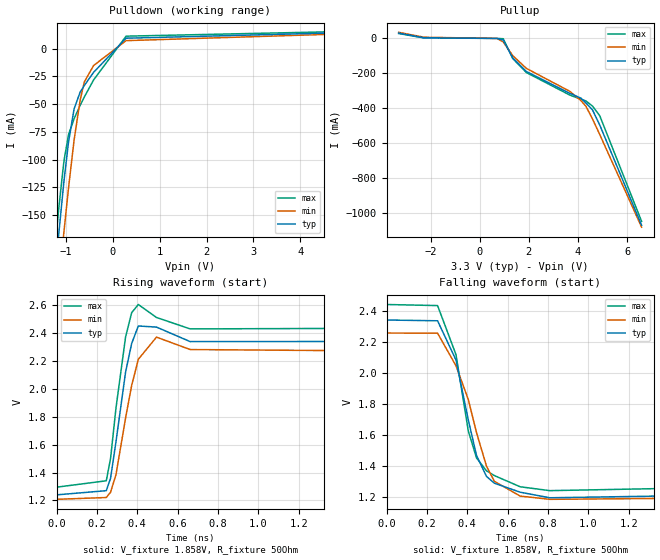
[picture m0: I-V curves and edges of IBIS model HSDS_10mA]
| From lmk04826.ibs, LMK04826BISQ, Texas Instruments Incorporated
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[Model]   HSDS_10mA
Model_type   Output
Polarity   Non-Inverting
Vmeas = 1.9
Vref = 1.9
Cref = 15pF
Rref = 50
|   typ   min   max
|   (nom PVT)   (slow PVT)   (fast PVT)
C_comp   2.777p   2.653p   2.902p
|C_comp (high state)   5.673p   4.718p   5.673p
|C_comp (low state)   2.777p   2.653p   2.902p
| Where   nom PVT is  Nominal Process, 3.3V, 27C
|   Fast PVT is Strong Process, 3.45V, -40C
|   Slow PVT is Weak Process, 3.15V, 125C
[Voltage Range]   3.3   3.15   3.45
[Temperature Range]   27   125   -40
[Pullup Reference]   3.3   3.15   3.45
[Pulldown Reference]   0   0   -0
[Power Clamp Reference]   3.3   3.15   3.45
[GND Clamp Reference]   0   0   0
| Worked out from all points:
|   slope of the pulldown table from 0 to 0.495 V, typ, clamps not added: 41.5 ohm
|   slope of the pullup table from 0 to 0.495 V, typ, clamps not added: 12.9 kohm
|   falling waveform, V_fixture 1.858V, R_fixture 50Ohm: 20-80 % time 116ps typ, 147ps min, 98.6ps max; typ from 2.34 V to 1.24 V
|   rising waveform, V_fixture 1.858V, R_fixture 50Ohm: 20-80 % time 62.3ps typ, 76.7ps min, 54.4ps max; typ from 1.24 V to 2.34 V
[Pulldown]
|   Voltage   I(typ)   I(min)   I(max)
-3.3V     -1.221A    -1.195A    -1.249A
-1.241V   -207.1mA   -250.6mA   -184.1mA
-1.152V   -166.7mA   -211.8mA   -143.8mA
-1.053V   -124.2mA   -169.6mA   -105.3mA
-1.033V   -116.2mA   -161.4mA   -98.96mA
-943.8mV  -84.03mA   -125.4mA   -77.43mA
-825mV    -54.22mA   -82.15mA   -63.11mA
-696.3mV  -39.16mA   -46.45mA   -51.06mA
-607.2mV  -33.16mA   -29.96mA   -43.52mA
-409.2mV  -21.36mA   -15.19mA   -28.15mA
283.8mV   9.398mA    7.213mA    11.25mA
6.59V     16.22mA    15.52mA    16.96mA
[Pullup]
|   Voltage   I(typ)   I(min)   I(max)
-3.3V     30.58mA    35.18mA    28.21mA
-2.27V    3.792mA    7.025mA    3.033mA
699.6mV   185.9uA    51.87uA    228.9uA
957mV     -9.234mA   -19.95mA   -1.603mA
1.343V    -111.3mA   -98.35mA   -115.3mA
1.897V    -189.5mA   -171.7mA   -195.4mA
3.67V     -315.3mA   -303.7mA   -325.1mA
4.125V    -342.8mA   -357.4mA   -348.9mA
4.323V    -370mA     -389mA     -358.8mA
4.59V     -409.9mA   -461.9mA   -388mA
4.887V    -497.2mA   -551.7mA   -443.9mA
6.59V     -1.072A    -1.083A    -1.05A
[Ramp]
R_load = 50
|   typ   min   max
dV/dt_r   0.660787/6.23189e-11   0.62932/7.6652e-11   0.687252/5.44213e-11
dV/dt_f   0.660787/1.15699e-10   0.62932/1.46839e-10   0.687252/9.8568e-11
[Falling Waveform]
V_fixture = 1.858V
V_fixture_min = 1.79V
V_fixture_max = 1.948V
R_fixture = 50Ohm
C_fixture = 0F
|   Time   V(typ)   V(min)   V(max)
0s        2.341V     2.257V     2.441V
253ps     2.336V     2.256V     2.434V
344.2ps   2.083V     2.046V     2.118V
405.4ps   1.696V     1.828V     1.625V
446ps     1.468V     1.615V     1.452V
495.4ps   1.333V     1.399V     1.369V
534.6ps   1.289V     1.301V     1.338V
662.2ps   1.231V     1.206V     1.266V
808.9ps   1.195V     1.185V     1.241V
3ns       1.24V      1.208V     1.295V
[Rising Waveform]
V_fixture = 1.858V
V_fixture_min = 1.79V
V_fixture_max = 1.948V
R_fixture = 50Ohm
C_fixture = 0F
|   Time   V(typ)   V(min)   V(max)
0s        1.24V      1.208V     1.295V
246.6ps   1.27V      1.221V     1.341V
267.8ps   1.359V     1.259V     1.501V
294.7ps   1.621V     1.385V     1.863V
342.2ps   2.12V      1.791V     2.372V
372.3ps   2.325V     2.024V     2.546V
405.4ps   2.451V     2.212V     2.605V
495.4ps   2.443V     2.371V     2.512V
662.2ps   2.339V     2.282V     2.43V
3ns       2.341V     2.257V     2.441V
